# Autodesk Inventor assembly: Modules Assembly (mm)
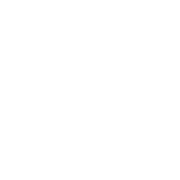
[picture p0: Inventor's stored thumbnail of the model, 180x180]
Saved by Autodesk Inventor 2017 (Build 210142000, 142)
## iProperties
Created: 2014-08
Part Number: Modules Assembly (mm)
Document SubType Name: Assembly
Designer: Wally
Author: Wally
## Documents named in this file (1)
- E:\!!AutoCAD Modules!!\Templates\Inventor\Metric Templates\Modules Assembly (mm).iam
